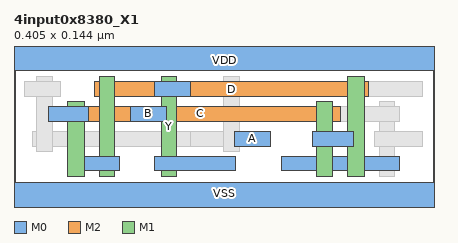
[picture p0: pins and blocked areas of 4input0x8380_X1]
MACRO 4input0x8380_X1
  CLASS CORE ;
  ORIGIN 0 0 ;
  FOREIGN 4input0x8380_X1 0 0 ;
  SIZE 0.4050 BY 0.1440 ;
  SYMMETRY X Y ;
  SITE coresite ;
  PIN A
    DIRECTION INPUT ;
    USE SIGNAL ;
    PORT
      LAYER M0 ;
        RECT 0.2130 0.0530 0.2470 0.0670 ;
    END
  END A
  PIN B
    DIRECTION INPUT ;
    USE SIGNAL ;
    PORT
      LAYER M0 ;
        RECT 0.1120 0.0770 0.1470 0.0910 ;
    END
  END B
  PIN C
    DIRECTION INPUT ;
    USE SIGNAL ;
    PORT
      LAYER M2 ;
        RECT 0.0450 0.0770 0.3150 0.0910 ;
      LAYER M1 ;
        RECT 0.0520 0.0240 0.0680 0.0960 ;
        RECT 0.2920 0.0240 0.3070 0.0960 ;
      LAYER M0 ;
        RECT 0.2880 0.0530 0.3270 0.0670 ;
        RECT 0.0330 0.0770 0.0720 0.0910 ;
    END
  END C
  PIN D
    DIRECTION INPUT ;
    USE SIGNAL ;
    PORT
      LAYER M2 ;
        RECT 0.0780 0.1010 0.3420 0.1150 ;
      LAYER M1 ;
        RECT 0.0820 0.0240 0.0970 0.1200 ;
        RECT 0.3220 0.0240 0.3380 0.1200 ;
      LAYER M0 ;
        RECT 0.2580 0.0290 0.3720 0.0430 ;
        RECT 0.0680 0.0290 0.1020 0.0430 ;
    END
  END D
  PIN Y
    DIRECTION OUTPUT ;
    USE SIGNAL ;
    PORT
      LAYER M1 ;
        RECT 0.1420 0.0240 0.1570 0.1200 ;
      LAYER M0 ;
        RECT 0.1350 0.1010 0.1700 0.1150 ;
        RECT 0.1350 0.0290 0.2140 0.0430 ;
    END
  END Y
  PIN VDD
    DIRECTION INOUT ;
    USE POWER ;
    SHAPE ABUTMENT ;
    PORT
      LAYER M0 ;
        RECT 0.0000 0.1260 0.4050 0.1620 ;
    END
  END VDD
  PIN VSS
    DIRECTION INOUT ;
    USE GROUND ;
    SHAPE ABUTMENT ;
    PORT
      LAYER M0 ;
        RECT 0.0000 -0.0180 0.4050 0.0180 ;
    END
  END VSS
  OBS
    LAYER M2 ;
      RECT 0.0180 0.0530 0.2250 0.0670 ;
    LAYER V1 ;
      RECT 0.0230 0.0530 0.0370 0.0670 ;
      RECT 0.2030 0.0530 0.2170 0.0670 ;
      RECT 0.0530 0.0770 0.0670 0.0910 ;
      RECT 0.2930 0.0770 0.3070 0.0910 ;
      RECT 0.0830 0.1010 0.0970 0.1150 ;
      RECT 0.3230 0.1010 0.3370 0.1150 ;
    LAYER M1 ;
      RECT 0.3520 0.0240 0.3670 0.0960 ;
      RECT 0.0220 0.0480 0.0370 0.1200 ;
      RECT 0.2020 0.0480 0.2170 0.1200 ;
    LAYER V0 ;
      RECT 0.0230 0.1010 0.0370 0.1150 ;
      RECT 0.2030 0.1010 0.2170 0.1150 ;
      RECT 0.0530 0.0770 0.0670 0.0910 ;
      RECT 0.2930 0.0530 0.3070 0.0670 ;
      RECT 0.1430 0.1010 0.1570 0.1150 ;
      RECT 0.1430 0.0290 0.1570 0.0430 ;
      RECT 0.3530 0.0770 0.3670 0.0910 ;
      RECT 0.3530 0.0530 0.3670 0.0670 ;
      RECT 0.0830 0.0290 0.0970 0.0430 ;
      RECT 0.3230 0.0290 0.3370 0.0430 ;
    LAYER M0 ;
      RECT 0.0550 0.0530 0.1700 0.0670 ;
      RECT 0.3480 0.0530 0.3940 0.0670 ;
      RECT 0.1680 0.0770 0.3720 0.0910 ;
      RECT 0.0100 0.1010 0.0450 0.1150 ;
      RECT 0.1900 0.1010 0.3940 0.1150 ;
  END
END 4input0x8380_X1
